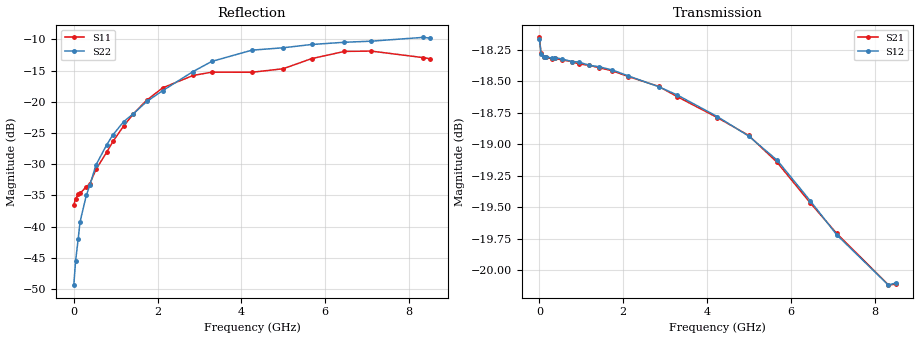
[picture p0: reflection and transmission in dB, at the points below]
! device id: pe43620
! dir: c:\dsa\pe43620\data\pe43620\085c\3p300v\18p00db
! Serial: 1001
! Insertion: A
! Temp: 85C
! VDD: 3.300V
! Attenuation Step: 18.00dB
! IDD: 9.957500e-03mA
! FILE NAME
! DATE 10-22-2008 15:09:21
! CORRECTED  DATA
#  Hz  S  RI  R  50.00
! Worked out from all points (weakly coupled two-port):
!   401 points, 300 kHz to 8.5 GHz, reference 50 ohm
!   highest |S21| = -18.15 dB at 300 kHz (marker M1); lowest = -20.1 dB at 8.33 GHz (marker M2)
!   lowest |S11| = -36.5 dB at 300 kHz (marker M3), VSWR 1.03, Z = 48.5 - j0.0375 ohm
!   |S11| at or under -10 dB: start of sweep to end of sweep
!   |S22| runs from -49.4 to -9.7 dB; largest |S21 - S12| = 0.00064
!   S11 on the Smith chart (normalised r, x): 300 kHz: 0.97, -0.00; 3.294 GHz: 0.79, -0.22; 8.5 GHz: 0.64, -0.01
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300000  -0.0149 -0.000386  0.1237 -0.00043  0.1235 -0.000224  -0.00336 -0.000526
4.27985e7  -0.0166 -0.00158  0.1219 -0.00115  0.1218 -0.00112  -0.00432 -0.00308
1.065463e8  -0.0181 -0.00186  0.1215 -0.00197  0.1215 -0.00196  -0.00548 -0.00587
1.490448e8  -0.0182 -0.00304  0.1215 -0.00261  0.1215 -0.00253  -0.00534 -0.0095
2.977895e8  -0.0202 -0.0051  0.1212 -0.00473  0.1213 -0.0047  -0.00574 -0.0168
3.827865e8  -0.0215 -0.00477  0.1212 -0.00605  0.1213 -0.00601  -0.00663 -0.0204
5.315313e8  -0.0274 -0.00889  0.1209 -0.00826  0.121 -0.00831  -0.0101 -0.0296
7.865223e8  -0.0364 -0.0153  0.1204 -0.012  0.1204 -0.0121  -0.0153 -0.0426
9.35267e8  -0.0428 -0.022  0.1199 -0.0143  0.1201 -0.0143  -0.0197 -0.0507
1.190258e9  -0.0553 -0.0322  0.1192 -0.0182  0.1192 -0.0183  -0.0272 -0.0637
1.424e9  -0.0672 -0.0436  0.1183 -0.022  0.1184 -0.022  -0.0371 -0.0712
1.742739e9  -0.0795 -0.0657  0.1169 -0.027  0.117 -0.027  -0.0519 -0.086
2.125225e9  -0.0916 -0.0913  0.1147 -0.033  0.1148 -0.0329  -0.0739 -0.0982
2.8477e9  -0.0993 -0.1284  0.11 -0.0435  0.11 -0.0434  -0.131 -0.1154
3.293934e9  -0.1024 -0.1388  0.1063 -0.0493  0.1065 -0.0493  -0.1616 -0.1345
4.25015e9  -0.12 -0.1234  0.098 -0.0601  0.098 -0.0603  -0.2162 -0.1422
4.993874e9  -0.1539 -0.1001  0.0915 -0.0665  0.0912 -0.0668  -0.2438 -0.1168
5.67385e9  -0.1994 -0.096  0.0833 -0.0724  0.0835 -0.0725  -0.2767 -0.0771
6.460072e9  -0.2331 -0.0982  0.0735 -0.0769  0.0739 -0.0768  -0.2986 -0.0204
7.09755e9  -0.2384 -0.0886  0.0653 -0.0802  0.0651 -0.0802  -0.3033 0.0349
8.330006e9  -0.2247 -0.0216  0.054 -0.0826  0.0538 -0.0827  -0.3065 0.1153
8.5e9  -0.2204 -0.0102  0.053 -0.0833  0.0529 -0.0835  -0.2967 0.1294
